VERSION 5.7 ;
  NOWIREEXTENSIONATPIN ON ;
  DIVIDERCHAR "/" ;
  BUSBITCHARS "[]" ;
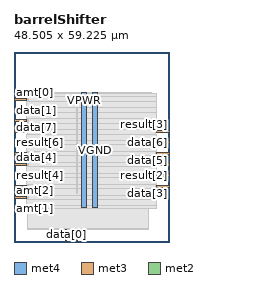
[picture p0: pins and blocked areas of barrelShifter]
MACRO barrelShifter
  CLASS BLOCK ;
  FOREIGN barrelShifter ;
  ORIGIN 0.000 0.000 ;
  SIZE 48.505 BY 59.225 ;
  PIN VGND
    DIRECTION INOUT ;
    USE GROUND ;
    PORT
      LAYER met4 ;
        RECT 24.340 10.640 25.940 46.480 ;
    END
  END VGND
  PIN VPWR
    DIRECTION INOUT ;
    USE POWER ;
    PORT
      LAYER met4 ;
        RECT 21.040 10.640 22.640 46.480 ;
    END
  END VPWR
  PIN amt[0]
    DIRECTION INPUT ;
    USE SIGNAL ;
    ANTENNAGATEAREA 0.196500 ;
    PORT
      LAYER met3 ;
        RECT 0.000 44.240 4.000 44.840 ;
    END
  END amt[0]
  PIN amt[1]
    DIRECTION INPUT ;
    USE SIGNAL ;
    ANTENNAGATEAREA 0.196500 ;
    PORT
      LAYER met3 ;
        RECT 0.000 10.240 4.000 10.840 ;
    END
  END amt[1]
  PIN amt[2]
    DIRECTION INPUT ;
    USE SIGNAL ;
    ANTENNAGATEAREA 0.196500 ;
    PORT
      LAYER met3 ;
        RECT 0.000 13.640 4.000 14.240 ;
    END
  END amt[2]
  PIN data[0]
    DIRECTION INPUT ;
    USE SIGNAL ;
    ANTENNAGATEAREA 0.213000 ;
    PORT
      LAYER met2 ;
        RECT 16.190 0.000 16.470 4.000 ;
    END
  END data[0]
  PIN data[1]
    DIRECTION INPUT ;
    USE SIGNAL ;
    ANTENNAGATEAREA 0.213000 ;
    PORT
      LAYER met3 ;
        RECT 0.000 40.840 4.000 41.440 ;
    END
  END data[1]
  PIN data[2]
    DIRECTION INPUT ;
    USE SIGNAL ;
    ANTENNAGATEAREA 0.213000 ;
    PORT
      LAYER met3 ;
        RECT 0.000 17.040 4.000 17.640 ;
    END
  END data[2]
  PIN data[3]
    DIRECTION INPUT ;
    USE SIGNAL ;
    ANTENNAGATEAREA 0.213000 ;
    PORT
      LAYER met3 ;
        RECT 44.505 17.040 48.505 17.640 ;
    END
  END data[3]
  PIN data[4]
    DIRECTION INPUT ;
    USE SIGNAL ;
    ANTENNAGATEAREA 0.213000 ;
    PORT
      LAYER met3 ;
        RECT 0.000 23.840 4.000 24.440 ;
    END
  END data[4]
  PIN data[5]
    DIRECTION INPUT ;
    USE SIGNAL ;
    ANTENNAGATEAREA 0.213000 ;
    PORT
      LAYER met3 ;
        RECT 44.505 27.240 48.505 27.840 ;
    END
  END data[5]
  PIN data[6]
    DIRECTION INPUT ;
    USE SIGNAL ;
    ANTENNAGATEAREA 0.213000 ;
    PORT
      LAYER met3 ;
        RECT 44.505 30.640 48.505 31.240 ;
    END
  END data[6]
  PIN data[7]
    DIRECTION INPUT ;
    USE SIGNAL ;
    ANTENNAGATEAREA 0.213000 ;
    PORT
      LAYER met3 ;
        RECT 0.000 37.440 4.000 38.040 ;
    END
  END data[7]
  PIN result[0]
    DIRECTION OUTPUT ;
    USE SIGNAL ;
    ANTENNADIFFAREA 0.445500 ;
    PORT
      LAYER met3 ;
        RECT 44.505 23.840 48.505 24.440 ;
    END
  END result[0]
  PIN result[1]
    DIRECTION OUTPUT ;
    USE SIGNAL ;
    ANTENNADIFFAREA 0.445500 ;
    PORT
      LAYER met2 ;
        RECT 19.410 0.000 19.690 4.000 ;
    END
  END result[1]
  PIN result[2]
    DIRECTION OUTPUT ;
    USE SIGNAL ;
    ANTENNADIFFAREA 0.445500 ;
    PORT
      LAYER met3 ;
        RECT 44.505 20.440 48.505 21.040 ;
    END
  END result[2]
  PIN result[3]
    DIRECTION OUTPUT ;
    USE SIGNAL ;
    ANTENNADIFFAREA 0.445500 ;
    PORT
      LAYER met3 ;
        RECT 44.505 34.040 48.505 34.640 ;
    END
  END result[3]
  PIN result[4]
    DIRECTION OUTPUT ;
    USE SIGNAL ;
    ANTENNADIFFAREA 0.445500 ;
    PORT
      LAYER met3 ;
        RECT 0.000 20.440 4.000 21.040 ;
    END
  END result[4]
  PIN result[5]
    DIRECTION OUTPUT ;
    USE SIGNAL ;
    ANTENNADIFFAREA 0.445500 ;
    PORT
      LAYER met3 ;
        RECT 0.000 27.240 4.000 27.840 ;
    END
  END result[5]
  PIN result[6]
    DIRECTION OUTPUT ;
    USE SIGNAL ;
    ANTENNADIFFAREA 0.445500 ;
    PORT
      LAYER met3 ;
        RECT 0.000 30.640 4.000 31.240 ;
    END
  END result[6]
  PIN result[7]
    DIRECTION OUTPUT ;
    USE SIGNAL ;
    ANTENNADIFFAREA 0.445500 ;
    PORT
      LAYER met3 ;
        RECT 0.000 34.040 4.000 34.640 ;
    END
  END result[7]
  OBS
      LAYER nwell ;
        RECT 5.330 10.795 42.970 46.430 ;
      LAYER li1 ;
        RECT 5.520 10.795 42.780 46.325 ;
      LAYER met1 ;
        RECT 4.210 10.640 42.780 46.480 ;
      LAYER met2 ;
        RECT 4.230 4.280 41.770 46.425 ;
        RECT 4.230 4.000 15.910 4.280 ;
        RECT 16.750 4.000 19.130 4.280 ;
        RECT 19.970 4.000 41.770 4.280 ;
      LAYER met3 ;
        RECT 3.990 45.240 44.505 46.405 ;
        RECT 4.400 43.840 44.505 45.240 ;
        RECT 3.990 41.840 44.505 43.840 ;
        RECT 4.400 40.440 44.505 41.840 ;
        RECT 3.990 38.440 44.505 40.440 ;
        RECT 4.400 37.040 44.505 38.440 ;
        RECT 3.990 35.040 44.505 37.040 ;
        RECT 4.400 33.640 44.105 35.040 ;
        RECT 3.990 31.640 44.505 33.640 ;
        RECT 4.400 30.240 44.105 31.640 ;
        RECT 3.990 28.240 44.505 30.240 ;
        RECT 4.400 26.840 44.105 28.240 ;
        RECT 3.990 24.840 44.505 26.840 ;
        RECT 4.400 23.440 44.105 24.840 ;
        RECT 3.990 21.440 44.505 23.440 ;
        RECT 4.400 20.040 44.105 21.440 ;
        RECT 3.990 18.040 44.505 20.040 ;
        RECT 4.400 16.640 44.105 18.040 ;
        RECT 3.990 14.640 44.505 16.640 ;
        RECT 4.400 13.240 44.505 14.640 ;
        RECT 3.990 11.240 44.505 13.240 ;
        RECT 4.400 10.375 44.505 11.240 ;
      LAYER met4 ;
        RECT 19.615 15.135 19.945 41.985 ;
  END
END barrelShifter
END LIBRARY

